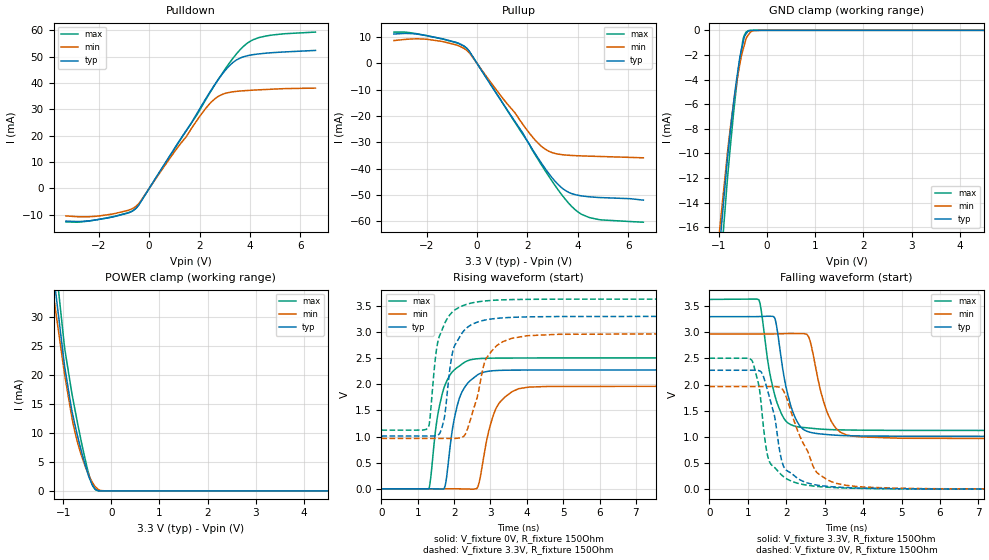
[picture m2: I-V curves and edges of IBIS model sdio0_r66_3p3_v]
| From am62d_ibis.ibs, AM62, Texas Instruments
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|   r66_3p3_v
[Model]   sdio0_r66_3p3_v
Model_type   I/O
Polarity   Non-Inverting
Enable   Active-High
Vinl = 0
Vinh = 0.8
Vmeas = 1.65
Vref = 3.3
Cref = 2pF
Rref = 100000
|   typ   min   max
C_comp   4.972pF   4.893pF   4.997pF
[Voltage Range]   3.3   2.97   3.63
[Temperature Range]   27   150   -40
[Pullup Reference]   3.3   2.97   3.63
[Pulldown Reference]   0   0   0
[Power Clamp Reference]   3.3   2.97   3.63
[GND Clamp Reference]   0   0   0
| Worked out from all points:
|   slope of the pulldown table from 0 to 0.495 V, typ, clamps not added: 65.7 ohm
|   slope of the pullup table from 0 to 0.495 V, typ, clamps not added: 67.2 ohm
|   GND clamp passes 1 mA (typ) near -0.50 V on its own axis
|   POWER clamp passes 1 mA (typ) near -0.39 V on its own axis
|   falling waveform, V_fixture 3.3V, R_fixture 150Ohm: 20-80 % time 372ps typ, 427ps min, 373ps max; typ from 3.3 V to 1.01 V
|   rising waveform, V_fixture 0V, R_fixture 150Ohm: 20-80 % time 360ps typ, 417ps min, 362ps max; typ from 0 V to 2.27 V
|   rising waveform, V_fixture 3.3V, R_fixture 150Ohm: 20-80 % time 346ps typ, 493ps min, 348ps max; typ from 1.01 V to 3.3 V
|   falling waveform, V_fixture 0V, R_fixture 150Ohm: 20-80 % time 382ps typ, 642ps min, 302ps max; typ from 2.27 V to 0 V
[Pulldown]
|   Voltage   I(typ)   I(min)   I(max)
-3.3V     -12.38mA   -10.4mA    -12.69mA
-1.924V   -11.64mA   -10.34mA   -11.61mA
-825mV    -9.287mA   -8.274mA   -9.181mA
-498.3mV  -7.317mA   -6.535mA   -7.277mA
1.917V    28.79mA    26.14mA    28.3mA
2.363V    35.87mA    31.75mA    35.58mA
2.779V    41.84mA    35.15mA    41.9mA
3.194V    46.68mA    36.49mA    47.74mA
3.442V    48.63mA    36.84mA    50.84mA
3.917V    50.43mA    37.21mA    55.3mA
4.363V    51.1mA     37.46mA    57.3mA
6.6V      52.41mA    38.1mA     59.37mA
[GND Clamp]
|   Voltage   I(typ)   I(min)   I(max)
-3.3V     -167.6mA   -127.2mA   -224.9mA
-1.013V   -18.75mA   -17.23mA   -21.53mA
-825mV    -10.45mA   -10mA      -12.11mA
-696.3mV  -5.878mA   -5.888mA   -6.706mA
-607.2mV  -3.274mA   -3.636mA   -3.487mA
-567.6mV  -2.201mA   -2.784mA   -2.433mA
-488.4mV  -791.1uA   -1.403mA   -562.6uA
-429mV    -244.1uA   -589.6uA   -116.9uA
-389.4mV  -55.69uA   -362.4uA   -20.74uA
-339.9mV  -13.09uA   -110.2uA   -2.892uA
-132mV    -51.23nA   -1.746uA   -80.05nA
6.6V      0A         0A         0A
[Pullup]
|   Voltage   I(typ)   I(min)   I(max)
-3.3V     11.17mA    8.678mA    11.89mA
-2.023V   10.59mA    9.208mA    10.6mA
-825mV    7.971mA    7.023mA    7.875mA
-409.2mV  5.742mA    4.947mA    5.744mA
1.502V    -22mA      -18.69mA   -22.32mA
2.056V    -30.43mA   -26.21mA   -30.36mA
2.363V    -35.1mA    -29.69mA   -35.55mA
2.838V    -41.68mA   -33.29mA   -42.71mA
3.472V    -48.02mA   -34.74mA   -51.2mA
4.026V    -50.09mA   -35.06mA   -56.53mA
4.462V    -50.64mA   -35.21mA   -58.53mA
6.6V      -51.89mA   -35.83mA   -60.27mA
[POWER Clamp]
|   Voltage   I(typ)   I(min)   I(max)
-3.3V     223mA      188.3mA    262.7mA
-1.201V   37.71mA    33.88mA    43.19mA
-1.191V   36.97mA    33.27mA    42.33mA
-1.152V   34.04mA    30.8mA     38.94mA
-983.4mV  22.42mA    20.88mA    25.69mA
-963.6mV  21.15mA    19.79mA    24.33mA
-805.2mV  13.3mA     12.07mA    16.24mA
-676.5mV  8.66mA     7.635mA    10.69mA
-488.4mV  3.032mA    3.154mA    3.565mA
-389.4mV  958.9uA    1.439mA    973.5uA
-290.4mV  115.2uA    394.7uA    56.84uA
6.6V      0A         0A         0A
[Ramp]
R_load = 150
|   typ   min   max
dV/dt_r   1.36452/3.60024e-10   1.17681/4.15033e-10   1.50275/3.61771e-10
dV/dt_f   1.37419/3.71447e-10   1.20297/4.24158e-10   1.50444/3.73096e-10
[Falling Waveform]
V_fixture = 3.3V
V_fixture_min = 2.97V
V_fixture_max = 3.63V
R_fixture = 150Ohm
C_fixture = 0F
|   Time   V(typ)   V(min)   V(max)
0s        3.3V       2.969V     3.63V
1.29ns    3.302V     2.969V     3.623V
1.545ns   3.307V     2.969V     2.334V
1.705ns   3.264V     2.97V      1.79V
1.96ns    2.082V     2.975V     1.333V
2.185ns   1.453V     2.977V     1.215V
2.58ns    1.097V     2.918V     1.171V
3.07ns    1.045V     1.464V     1.142V
3.565ns   1.024V     1.039V     1.132V
10ns      1.009V     964.3mV    1.122V
[Rising Waveform]
V_fixture = 0V
V_fixture_min = 0V
V_fixture_max = 0V
R_fixture = 150Ohm
C_fixture = 0F
|   Time   V(typ)   V(min)   V(max)
0s        421.7uV    878.7uV    305.1uV
1.305ns   333.2uV    642.3uV    6.835mV
1.525ns   -1.496mV   481.4uV    1.308V
1.725ns   4.128mV    457.7uV    1.938V
2.035ns   1.441V     -27.97uV   2.293V
2.37ns    2.018V     -3.796mV   2.45V
2.66ns    2.186V     53.71mV    2.489V
3.16ns    2.263V     1.546V     2.5V
3.775ns   2.271V     1.915V     2.502V
10ns      2.275V     1.962V     2.505V
[Rising Waveform]
V_fixture = 3.3V
V_fixture_min = 2.97V
V_fixture_max = 3.63V
R_fixture = 150Ohm
C_fixture = 0F
|   Time   V(typ)   V(min)   V(max)
0s        1.009V     964.3mV    1.122V
1.285ns   1.009V     964.2mV    1.167V
1.49ns    1.014V     964mV      2.532V
1.59ns    1.048V     964mV      2.912V
1.735ns   1.375V     964mV      3.155V
1.96ns    2.621V     963.9mV    3.387V
2.285ns   3.037V     1.021V     3.516V
2.865ns   3.23V      2.468V     3.595V
3.565ns   3.279V     2.874V     3.62V
10ns      3.3V       2.969V     3.63V
[Falling Waveform]
|Gnd
V_fixture = 0V
V_fixture_min = 0V
V_fixture_max = 0V
R_fixture = 150Ohm
C_fixture = 0F
|   Time   V(typ)   V(min)   V(max)
0s        2.275V     1.962V     2.505V
1.1ns     2.275V     1.962V     2.47V
1.295ns   2.266V     1.962V     1.954V
1.355ns   2.236V     1.962V     1.573V
1.56ns    1.767V     1.962V     530.2mV
1.9ns     500.3mV    1.912V     257.4mV
2.21ns    257.7mV    1.294V     132.9mV
2.755ns   83.96mV    358.1mV    56.31mV
3.34ns    38.74mV    104.8mV    27.67mV
10ns      420.5uV    878.9uV    305.3uV
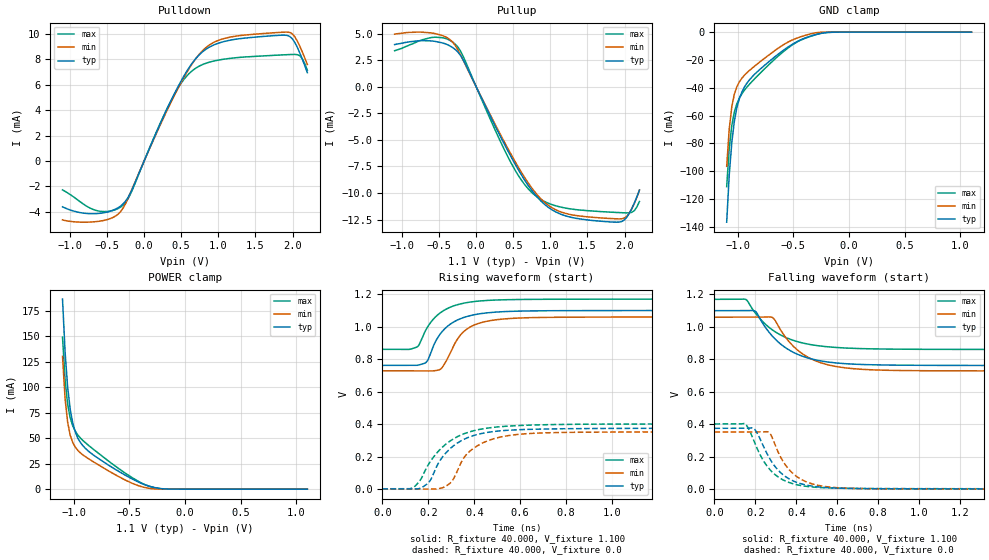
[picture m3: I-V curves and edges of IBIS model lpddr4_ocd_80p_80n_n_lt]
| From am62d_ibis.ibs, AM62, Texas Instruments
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|   Model lpddr4_ocd_80p_80n_n_lt
[Model] lpddr4_ocd_80p_80n_n_lt
Model_type I/O
Polarity   Non-Inverting
Enable   Active-High
Vinl =  0.113V
Vinh =  0.253V
Vmeas =  0.183V
C_comp   3.217pF   3.046pF   3.235pF
C_comp_pullup   0.301pF   0.290pF   0.305pF
C_comp_pulldown   1.279pF   1.206pF   1.283pF
[Model Spec]
Vinh   0.253V   0.247V   0.265V
Vinl   0.113V   0.107V   0.125V
Vmeas   0.183V   0.176V   0.195V
[Temperature Range]   25.000   -40.000   -40.000
[Voltage Range]   1.100V   1.060V   1.170V
[Pullup Reference]   1.100V   1.060V   1.170V
[Pulldown Reference]   0.0V   0.0V   0.0V
[C Comp Corner]
C_comp_pullup   0.301pF   0.290pF   0.305pF
C_comp_pulldown   1.279pF   1.206pF   1.283pF
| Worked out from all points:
|   slope of the pulldown table from 0 to 0.165 V, typ, clamps not added: 73.7 ohm
|   slope of the pullup table from 0 to 0.165 V, typ, clamps not added: 68.8 ohm
|   GND clamp passes 1 mA (typ) near -0.26 V on its own axis
|   POWER clamp passes 1 mA (typ) near -0.24 V on its own axis
|   rising waveform, R_fixture 40.000, V_fixture 1.100: 20-80 % time 106ps typ, 96.8ps min, 107ps max; typ from 0.762 V to 1.1 V
|   rising waveform, R_fixture 40.000, V_fixture 0.0: 20-80 % time 130ps typ, 122ps min, 150ps max; typ from 0.001 V to 0.375 V
|   falling waveform, R_fixture 40.000, V_fixture 1.100: 20-80 % time 178ps typ, 169ps min, 186ps max; typ from 1.1 V to 0.762 V
|   falling waveform, R_fixture 40.000, V_fixture 0.0: 20-80 % time 122ps typ, 117ps min, 119ps max; typ from 0.375 V to 0.001 V
[Pulldown]
|Voltage   I(typ)   I(min)   I(max)
-1.1V     -3.6mA     -4.624mA   -2.269mA
-624mV    -4.125mA   -4.747mA   -3.918mA
-284mV    -3.371mA   -3.705mA   -3.47mA
-181mV    -2.473mA   -2.447mA   -2.564mA
227mV     3.052mA    2.956mA    3.092mA
465mV     5.929mA    5.803mA    5.81mA
703mV     8.095mA    8.097mA    7.323mA
907mV     9.036mA    9.222mA    7.813mA
1.928V    9.87mA     10.13mA    8.358mA
1.996V    9.616mA    10mA       8.375mA
2.098V    8.498mA    9.025mA    8.273mA
2.2V      6.944mA    7.59mA     7.136mA
[Pullup]
|Voltage   I(typ)   I(min)   I(max)
-1.1V     3.978mA    4.962mA    3.399mA
-590mV    4.31mA     5.055mA    4.652mA
-284mV    3.52mA     3.909mA    4.021mA
-147mV    2.159mA    2.092mA    2.416mA
295mV     -4.237mA   -4.07mA    -4.673mA
533mV     -7.385mA   -7.144mA   -7.949mA
737mV     -9.638mA   -9.409mA   -9.867mA
1.009V    -11.52mA   -11.33mA   -11.06mA
1.315V    -12.34mA   -12.09mA   -11.54mA
1.928V    -12.73mA   -12.44mA   -11.84mA
2.064V    -11.91mA   -11.88mA   -11.86mA
2.2V      -9.724mA   -9.725mA   -10.8mA
[GND_clamp]
|Voltage   I(typ)   I(min)   I(max)
-1.1V     -136.6mA   -96.46mA   -111.1mA
-1.077V   -102.6mA   -69.55mA   -83.57mA
-1.054V   -79.22mA   -53.64mA   -67.05mA
-1.031V   -63.93mA   -44.56mA   -57.36mA
-1.008V   -54.04mA   -39.16mA   -51.37mA
-985mV    -47.47mA   -35.61mA   -47.28mA
-940mV    -39.36mA   -30.91mA   -41.63mA
-894mV    -34.19mA   -27.47mA   -37.37mA
-642mV    -16.16mA   -11.85mA   -17.57mA
-435mV    -5.566mA   -3.394mA   -5.8mA
-206mV    -368.5uA   -17.49uA   -340.6uA
1.1V      0A         0A         0A
[POWER_clamp]
|Voltage   I(typ)   I(min)   I(max)
-1.1V     186.7mA    130.4mA    149.4mA
-1.077V   134.7mA    89.1mA     107.4mA
-1.054V   100.3mA    65.79mA    83.44mA
-1.031V   78.51mA    53mA       69.97mA
-1.008V   64.87mA    45.79mA    62.12mA
-963mV    50.23mA    38.14mA    53.29mA
-917mV    42.67mA    33.66mA    47.79mA
-848mV    35.63mA    28.64mA    41.42mA
-481mV    10.42mA    6.123mA    11.78mA
-367mV    4.613mA    1.825mA    4.83mA
-252mV    1.166mA    119.4uA    981uA
1.1V      0A         0A         0A
[Ramp]
| variable   typ   min   max
dV/dt_r   0.232/98.871p   0.220/90.180p   0.253/0.105n
dV/dt_f   0.232/0.216n   0.219/0.206n   0.253/0.227n
R_load = 40.000
[Rising Waveform]
R_fixture= 40.000
V_fixture= 1.100
V_fixture_min= 1.060
V_fixture_max= 1.170
|time   V(typ)   V(min)   V(max)
0s        761.9mV    728.5mV    860.7mV
148ps     761.7mV    728.5mV    873.1mV
186ps     776.2mV    728.3mV    971.1mV
249ps     949.6mV    735.3mV    1.082V
296ps     1.016V     838.9mV    1.12V
327ps     1.041V     924.2mV    1.135V
361ps     1.06V      978mV      1.147V
426ps     1.08V      1.023V     1.158V
526ps     1.092V     1.047V     1.166V
5ns       1.1V       1.06V      1.17V
[Rising Waveform]
R_fixture= 40.000
V_fixture= 0.0
V_fixture_min= 0.0
V_fixture_max= 0.0
|time   V(typ)   V(min)   V(max)
0s        1.134mV    70.35uV    2.405mV
137ps     1.013mV    70.11uV    12.8mV
166ps     6.25mV     71.57uV    57.66mV
203ps     43.73mV    19.24uV    157.7mV
267ps     207.6mV    11.72mV    265.8mV
303ps     259.2mV    49.71mV    304.1mV
352ps     304.6mV    187.3mV    339.2mV
393ps     328.2mV    247.4mV    358.1mV
568ps     364.3mV    333.5mV    389.9mV
5ns       375.3mV    354.1mV    401.8mV
[Falling Waveform]
R_fixture= 40.000
V_fixture= 1.100
V_fixture_min= 1.060
V_fixture_max= 1.170
|time   V(typ)   V(min)   V(max)
0s        1.1V       1.06V      1.17V
151ps     1.1V       1.06V      1.17V
197ps     1.098V     1.06V      1.09V
281ps     945.9mV    1.059V     983.4mV
364ps     858.3mV    909.9mV    926.8mV
438ps     815.8mV    827.5mV    898.9mV
536ps     787mV      772.7mV    879.6mV
668ps     771.2mV    743.8mV    868.4mV
1.117ns   762.7mV    729.4mV    861.5mV
5ns       761.9mV    728.5mV    860.7mV
[Falling Waveform]
R_fixture= 40.000
V_fixture= 0.0
V_fixture_min= 0.0
V_fixture_max= 0.0
|time   V(typ)   V(min)   V(max)
0s        375.1mV    352.2mV    401.8mV
151ps     375mV      352.2mV    401.8mV
197ps     368.4mV    352.2mV    285.1mV
264ps     202.2mV    351.1mV    131.1mV
312ps     116.1mV    226.4mV    74.67mV
370ps     59.78mV    113.6mV    38.76mV
429ps     31.19mV    56.91mV    20.99mV
507ps     14.17mV    23.58mV    10.68mV
877ps     2.46mV     1.451mV    3.46mV
5ns       1.147mV    70.82uV    2.412mV
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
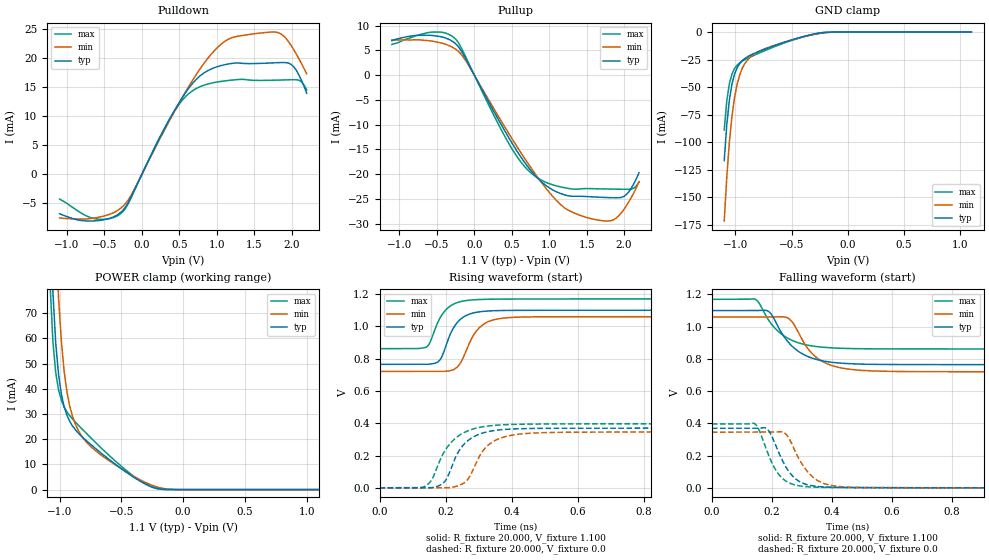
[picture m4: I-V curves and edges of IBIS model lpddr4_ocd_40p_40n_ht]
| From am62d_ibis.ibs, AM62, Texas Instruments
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|LPDDR4 ********** End LPDDR4 LT Models
|LPDDR4 ********** Begin LPDDR4 HT Models
|   Model lpddr4_ocd_40p_40n_ht
[Model] lpddr4_ocd_40p_40n_ht
Model_type I/O
Polarity   Non-Inverting
Enable   Active-High
Vinl =  0.113V
Vinh =  0.253V
Vmeas =  0.183V
C_comp   2.128pF   2.068pF   2.214pF
[Model Spec]
Vinh   0.253V   0.247V   0.265V
Vinl   0.113V   0.107V   0.125V
Vmeas   0.183V   0.176V   0.195V
[Temperature Range]   25.000   0.125k   -40.000
[Voltage Range]   1.100V   1.060V   1.170V
[Pullup Reference]   1.100V   1.060V   1.170V
[Pulldown Reference]   0.0V   0.0V   0.0V
[C Comp Corner]
C_comp   2.128pF   2.068pF   2.214pF
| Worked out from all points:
|   slope of the pulldown table from 0 to 0.165 V, typ, clamps not added: 37.7 ohm
|   slope of the pullup table from 0 to 0.165 V, typ, clamps not added: 35.3 ohm
|   GND clamp passes 1 mA (typ) near -0.26 V on its own axis
|   POWER clamp passes 1 mA (typ) near -0.24 V on its own axis
|   rising waveform, R_fixture 20.000, V_fixture 1.100: 20-80 % time 46.6ps typ, 53.4ps min, 46.5ps max; typ from 0.765 V to 1.1 V
|   rising waveform, R_fixture 20.000, V_fixture 0.0: 20-80 % time 62ps typ, 64.4ps min, 71.1ps max; typ from 0.001 V to 0.37 V
|   falling waveform, R_fixture 20.000, V_fixture 1.100: 20-80 % time 89.6ps typ, 83.9ps min, 89.3ps max; typ from 1.1 V to 0.765 V
|   falling waveform, R_fixture 20.000, V_fixture 0.0: 20-80 % time 62.9ps typ, 69.5ps min, 58.3ps max; typ from 0.37 V to 0.001 V
[Pulldown]
|Voltage   I(typ)   I(min)   I(max)
-1.1V     -6.798mA   -7.521mA   -4.288mA
-658mV    -8.043mA   -7.581mA   -7.565mA
-284mV    -6.568mA   -5.855mA   -6.785mA
-147mV    -3.977mA   -3.669mA   -4.118mA
261mV     6.826mA    6.606mA    6.92mA
533mV     13.06mA    13.05mA    12.63mA
805mV     17.19mA    18.64mA    15.19mA
1.145V    18.92mA    23.14mA    16.1mA
1.826V    19.17mA    24.29mA    16.17mA
2.03V     18.41mA    21.33mA    16.24mA
2.132V    16.08mA    18.96mA    15.87mA
2.2V      13.9mA     17.26mA    14.49mA
[Pullup]
|Voltage   I(typ)   I(min)   I(max)
-1.1V     6.941mA    7.09mA     6.183mA
-590mV    8.025mA    6.904mA    8.63mA
-284mV    6.736mA    5.549mA    7.721mA
-113mV    3.254mA    2.882mA    3.632mA
329mV     -9.187mA   -8.507mA   -10.13mA
601mV     -16.06mA   -15.17mA   -17.12mA
907mV     -21.69mA   -21.89mA   -21.3mA
1.247V    -24.36mA   -27.22mA   -22.87mA
1.588V    -24.61mA   -29.09mA   -22.95mA
1.86V     -24.78mA   -29.21mA   -23.03mA
2.03V     -24.15mA   -26.41mA   -23.07mA
2.2V      -19.71mA   -21.51mA   -21.55mA
[GND_clamp]
|Voltage   I(typ)   I(min)   I(max)
-1.1V     -116.8mA   -171.6mA   -88.94mA
-1.077V   -83.96mA   -131.3mA   -62.39mA
-1.054V   -61.6mA    -99.87mA   -46.82mA
-1.031V   -47.19mA   -76.34mA   -38.11mA
-1.008V   -38.16mA   -59.32mA   -33.12mA
-985mV    -32.43mA   -47.3mA    -30.04mA
-940mV    -26mA      -32.95mA   -26.37mA
-894mV    -22.48mA   -25.52mA   -23.91mA
-848mV    -20.08mA   -21.13mA   -21.75mA
-619mV    -11.17mA   -10.91mA   -11.97mA
-229mV    -598.7uA   -1.001mA   -573.1uA
1.1V      0A         0A         0A
[POWER_clamp]
|Voltage   I(typ)   I(min)   I(max)
-1.1V     158.5mA    248.7mA    122.8mA
-1.077V   110.5mA    184.5mA    81.81mA
-1.054V   78.43mA    136mA      58.82mA
-1.031V   58.13mA    100.8mA    46.37mA
-1.008V   45.61mA    75.97mA    39.54mA
-985mV    37.81mA    58.74mA    35.43mA
-963mV    32.84mA    46.93mA    32.78mA
-940mV    29.44mA    38.74mA    30.81mA
-871mV    23.65mA    25.79mA    26.71mA
-642mV    13.62mA    12.94mA    15.51mA
-206mV    448.9uA    953.5uA    285.6uA
1.1V      0A         0A         0A
[Ramp]
| variable   typ   min   max
dV/dt_r   0.222/62.046p   0.208/64.382p   0.238/71.086p
dV/dt_f   0.201/89.565p   0.204/84.088p   0.185/89.279p
R_load = 20.000
[Rising Waveform]
R_fixture= 20.000
V_fixture= 1.100
V_fixture_min= 1.060
V_fixture_max= 1.170
|time   V(typ)   V(min)   V(max)
0s        764.9mV    720.8mV    861.9mV
142ps     764.7mV    720.8mV    872.2mV
152ps     766.3mV    720.8mV    898.4mV
183ps     793.7mV    720.5mV    1.052V
223ps     988.3mV    731.4mV    1.137V
245ps     1.044V     775.2mV    1.153V
295ps     1.088V     976.5mV    1.165V
350ps     1.097V     1.043V     1.168V
548ps     1.099V     1.059V     1.169V
5ns       1.1V       1.06V      1.17V
[Rising Waveform]
R_fixture= 20.000
V_fixture= 0.0
V_fixture_min= 0.0
V_fixture_max= 0.0
|time   V(typ)   V(min)   V(max)
0s        557.8uV    842.1uV    1.185mV
141ps     573.8uV    838.4uV    14.95mV
160ps     2.108mV    832.9uV    58.59mV
196ps     36.82mV    899.9uV    224.3mV
243ps     238.1mV    17.6mV     327.8mV
269ps     296mV      59.48mV    355.2mV
323ps     346.1mV    254.3mV    381.9mV
390ps     363.5mV    322.2mV    392.2mV
650ps     369.6mV    345.5mV    396.8mV
5ns       370.3mV    347mV      397.2mV
[Falling Waveform]
R_fixture= 20.000
V_fixture= 1.100
V_fixture_min= 1.060
V_fixture_max= 1.170
|time   V(typ)   V(min)   V(max)
0s        1.1V       1.06V      1.17V
146ps     1.1V       1.06V      1.169V
192ps     1.09V      1.06V      1.033V
249ps     916.9mV    1.058V     932.6mV
270ps     874.6mV    1.024V     912.9mV
294ps     840.3mV    943.4mV    897mV
351ps     795.7mV    805.4mV    876.4mV
403ps     778.6mV    757.3mV    868.4mV
477ps     769.3mV    732.6mV    864mV
5ns       764.9mV    720.8mV    861.9mV
[Falling Waveform]
R_fixture= 20.000
V_fixture= 0.0
V_fixture_min= 0.0
V_fixture_max= 0.0
|time   V(typ)   V(min)   V(max)
0s        369.8mV    345.9mV    396.8mV
144ps     369.7mV    345.9mV    396.8mV
188ps     358.1mV    345.8mV    208.2mV
212ps     267.5mV    347.2mV    113.7mV
238ps     159.8mV    344.9mV    54.66mV
280ps     54.64mV    217.9mV    17.41mV
339ps     12.17mV    63.51mV    5.223mV
402ps     3.902mV    14mV       2.716mV
539ps     1.466mV    2.153mV    1.722mV
5ns       557.6uV    836uV      1.186mV
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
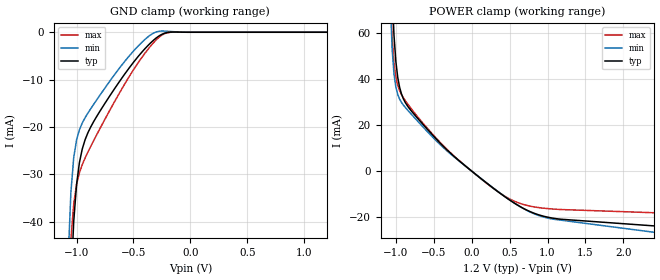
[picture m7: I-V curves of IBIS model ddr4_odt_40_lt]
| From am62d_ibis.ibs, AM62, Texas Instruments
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|   Model ddr4_odt_40_lt
[Model] ddr4_odt_40_lt
Model_type Input
Polarity   Non-Inverting
Enable   Active-High
Vinl =  0.700V
Vinh =  0.900V
C_comp   2.181pF   1.976pF   2.362pF
[Model Spec]
Vinh   0.900V   0.820V   0.980V
Vinl   0.700V   0.620V   0.780V
[Temperature Range]   25.000   -40.000   -40.000
[Voltage Range]   1.200V   1.140V   1.260V
[C Comp Corner]
C_comp   2.181pF   1.976pF   2.362pF
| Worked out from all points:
|   GND clamp passes 1 mA (typ) near -0.29 V on its own axis
|   POWER clamp passes 1 mA (typ) near -0.04 V on its own axis
[GND_clamp]
|Voltage   I(typ)   I(min)   I(max)
-1.2V     -384.2mA   -349.1mA   -361.3mA
-1.075V   -75.51mA   -48.36mA   -58.73mA
-1.05V    -53.29mA   -33.77mA   -43.81mA
-1.025V   -39.9mA    -26.45mA   -36.16mA
-1V       -32.1mA    -22.71mA   -32.11mA
-975mV    -27.5mA    -20.58mA   -29.67mA
-950mV    -24.63mA   -19.15mA   -27.94mA
-875mV    -19.96mA   -16.12mA   -24.06mA
-750mV    -14.97mA   -11.74mA   -18.32mA
-350mV    -2.263mA   -565uA     -2.938mA
-175mV    27.08uA    163.2uA    -8.172uA
1.2V      0A         0A         0A
[POWER_clamp]
|Voltage   I(typ)   I(min)   I(max)
-1.2V     599.9mA    618.7mA    627.1mA
-1.075V   111.9mA    76.22mA    81.9mA
-1.05V    79.07mA    53.64mA    58.84mA
-1.025V   59.3mA     42.37mA    47.11mA
-1V       47.67mA    36.58mA    40.91mA
-950mV    36.4mA     31.3mA     34.98mA
-900mV    31.43mA    28.72mA    31.9mA
-325mV    9.238mA    8.792mA    9.428mA
375mV     -9.667mA   -9.572mA   -9.635mA
650mV     -15.66mA   -15.71mA   -14.21mA
1V        -20.04mA   -20.43mA   -16.31mA
2.4V      -23.84mA   -26.61mA   -18.12mA
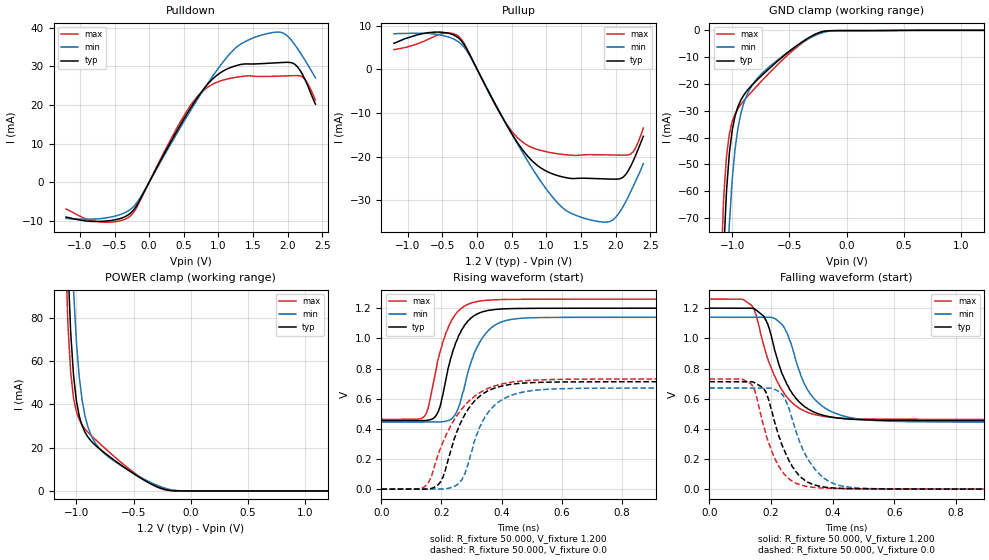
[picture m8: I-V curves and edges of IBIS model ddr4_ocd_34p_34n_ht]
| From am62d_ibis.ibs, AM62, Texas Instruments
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|DDR4 ********** End DDR4 LT Models
|DDR4 ********** Begin DDR4 HT Models
|   Model ddr4_ocd_34p_34n_ht
[Model] ddr4_ocd_34p_34n_ht
Model_type I/O
Polarity   Non-Inverting
Enable   Active-High
Vinl =  0.700V
Vinh =  0.900V
Vmeas =  0.600V
C_comp   2.033pF   1.992pF   2.166pF
[Model Spec]
Vinh   0.900V   0.820V   0.980V
Vinl   0.700V   0.620V   0.780V
Vmeas   0.600V   NA   NA
[Temperature Range]   25.000   0.125k   -40.000
[Voltage Range]   1.200V   1.140V   1.260V
[Pullup Reference]   1.200V   1.140V   1.260V
[Pulldown Reference]   0.0V   0.0V   0.0V
[C Comp Corner]
C_comp   2.033pF   1.992pF   2.166pF
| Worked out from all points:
|   slope of the pulldown table from 0 to 0.18 V, typ, clamps not added: 29.6 ohm
|   slope of the pullup table from 0 to 0.18 V, typ, clamps not added: 32.3 ohm
|   GND clamp passes 1 mA (typ) near -0.25 V on its own axis
|   POWER clamp passes 1 mA (typ) near -0.25 V on its own axis
|   rising waveform, R_fixture 50.000, V_fixture 1.200: 20-80 % time 64.1ps typ, 72ps min, 64.6ps max; typ from 0.455 V to 1.2 V
|   rising waveform, R_fixture 50.000, V_fixture 0.0: 20-80 % time 89.4ps typ, 83.8ps min, 116ps max; typ from 0.001 V to 0.713 V
|   falling waveform, R_fixture 50.000, V_fixture 1.200: 20-80 % time 84ps typ, 88.9ps min, 88.7ps max; typ from 1.2 V to 0.455 V
|   falling waveform, R_fixture 50.000, V_fixture 0.0: 20-80 % time 76.3ps typ, 83.7ps min, 70.4ps max; typ from 0.713 V to 0.001 V
[Pulldown]
|Voltage   I(typ)   I(min)   I(max)
-1.2V     -9.006mA   -9.388mA   -6.947mA
-718mV    -10.14mA   -9.441mA   -10.24mA
-272mV    -8.055mA   -7.047mA   -8.751mA
-124mV    -4.222mA   -3.864mA   -4.561mA
359mV     11.91mA    11.33mA    12.65mA
656mV     20.78mA    20.23mA    21.27mA
990mV     27.82mA    29.26mA    25.93mA
1.361V    30.56mA    36.13mA    27.4mA
1.955V    30.99mA    38.38mA    27.48mA
2.14V     29.85mA    34.61mA    27.57mA
2.252V    26.49mA    31.49mA    26.52mA
2.4V      20.19mA    26.99mA    21.28mA
[Pullup]
|Voltage   I(typ)   I(min)   I(max)
-1.2V     5.943mA    8.121mA    4.494mA
-606mV    8.496mA    8.044mA    7.591mA
-421mV    8.267mA    7.423mA    8.349mA
-235mV    6.663mA    5.861mA    7.043mA
322mV     -9.774mA   -9.622mA   -9.826mA
544mV     -15.84mA   -15.99mA   -14.99mA
878mV     -22.09mA   -24.67mA   -18.39mA
1.324V    -24.91mA   -32.69mA   -19.62mA
1.955V    -25.14mA   -34.51mA   -19.61mA
2.103V    -24.74mA   -31.54mA   -19.65mA
2.252V    -21.04mA   -26.85mA   -18.9mA
2.4V      -15.33mA   -21.56mA   -13.45mA
[GND_clamp]
|Voltage   I(typ)   I(min)   I(max)
-1.2V     -396.3mA   -450.8mA   -370.1mA
-1.1V     -118.3mA   -172.8mA   -91.09mA
-1.075V   -83.02mA   -129.3mA   -62.73mA
-1.05V    -59.94mA   -96.19mA   -46.97mA
-1.025V   -45.76mA   -72.24mA   -38.62mA
-1V       -37.22mA   -55.56mA   -33.98mA
-975mV    -31.95mA   -44.18mA   -31.14mA
-925mV    -26.07mA   -31.12mA   -27.64mA
-775mV    -18.22mA   -17.64mA   -20.37mA
-425mV    -5.392mA   -5.54mA    -5.964mA
-175mV    -232.3uA   -493.9uA   -237.1uA
1.2V      0A         0A         0A
[POWER_clamp]
|Voltage   I(typ)   I(min)   I(max)
-1.2V     594.8mA    732.7mA    623.3mA
-1.1V     157.8mA    248.4mA    121.5mA
-1.075V   106.2mA    179.2mA    77.8mA
-1.05V    73.23mA    128.5mA    54.67mA
-1.025V   53.34mA    92.89mA    42.85mA
-1V       41.61mA    68.72mA    36.57mA
-975mV    34.56mA    52.6mA     32.87mA
-925mV    27.12mA    34.66mA    28.61mA
-825mV    20.64mA    21.33mA    23.28mA
-675mV    14.44mA    14mA       16.15mA
-200mV    388.2uA    876.1uA    237.4uA
1.2V      0A         0A         0A
[Ramp]
| variable   typ   min   max
dV/dt_r   0.427/89.561p   0.432/87.187p   0.437/0.117n
dV/dt_f   0.447/84.662p   0.446/91.796p   0.478/88.149p
R_load = 60.000
[Rising Waveform]
R_fixture= 50.000
V_fixture= 1.200
V_fixture_min= 1.140
V_fixture_max= 1.260
|time   V(typ)   V(min)   V(max)
0s        455.2mV    445.7mV    463.4mV
143ps     455.3mV    445.7mV    483.7mV
155ps     457.8mV    445.7mV    532.8mV
190ps     518mV      445.7mV    868.7mV
236ps     900.2mV    471.1mV    1.127V
276ps     1.085V     674mV      1.213V
333ps     1.173V     991.7mV    1.249V
396ps     1.194V     1.106V     1.257V
506ps     1.199V     1.137V     1.259V
3ns       1.2V       1.14V      1.26V
[Rising Waveform]
R_fixture= 50.000
V_fixture= 0.0
V_fixture_min= 0.0
V_fixture_max= 0.0
|time   V(typ)   V(min)   V(max)
0s        1.434mV    1.61mV     2.494mV
139ps     1.37mV     1.6mV      11.11mV
162ps     4.513mV    1.591mV    65.51mV
187ps     27.16mV    1.528mV    218.5mV
205ps     79.98mV    2.312mV    314.7mV
255ps     399.3mV    34.26mV    499.3mV
278ps     497.6mV    103.8mV    556.5mV
345ps     640.8mV    480.6mV    659.5mV
444ps     698.5mV    630.4mV    712.7mV
3ns       712.8mV    671.4mV    731.1mV
[Falling Waveform]
R_fixture= 50.000
V_fixture= 1.200
V_fixture_min= 1.140
V_fixture_max= 1.260
|time   V(typ)   V(min)   V(max)
0s        1.2V       1.14V      1.26V
139ps     1.199V     1.14V      1.213V
184ps     1.12V      1.14V      895.5mV
217ps     885.3mV    1.124V     728.2mV
251ps     698.1mV    1.041V     612mV
279ps     606.4mV    868.3mV    555.6mV
315ps     539.6mV    669.7mV    512.9mV
380ps     484.7mV    532.7mV    480.4mV
645ps     456.1mV    448.3mV    463.9mV
3ns       455.2mV    445.6mV    463.4mV
[Falling Waveform]
R_fixture= 50.000
V_fixture= 0.0
V_fixture_min= 0.0
V_fixture_max= 0.0
|time   V(typ)   V(min)   V(max)
0s        712.8mV    671.3mV    731.1mV
136ps     712.6mV    671.3mV    697.2mV
183ps     647.6mV    671.3mV    370.5mV
228ps     339mV      644.8mV    144.8mV
251ps     221.3mV    574.7mV    82.29mV
278ps     123.6mV    401.8mV    44.64mV
331ps     36.75mV    165.7mV    14.79mV
402ps     9.12mV     38.96mV    6.159mV
512ps     3.266mV    6.029mV    3.739mV
3ns       1.433mV    1.604mV    2.494mV
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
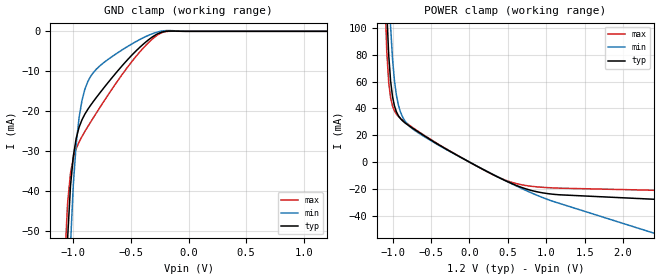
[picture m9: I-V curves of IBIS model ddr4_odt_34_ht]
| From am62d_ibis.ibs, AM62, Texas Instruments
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|   Model ddr4_odt_34_ht
[Model] ddr4_odt_34_ht
Model_type Input
Polarity   Non-Inverting
Enable   Active-High
Vinl =  0.700V
Vinh =  0.900V
C_comp   2.071pF   1.974pF   2.274pF
[Model Spec]
Vinh   0.900V   0.820V   0.980V
Vinl   0.700V   0.620V   0.780V
[Temperature Range]   25.000   0.125k   -40.000
[Voltage Range]   1.200V   1.140V   1.260V
[C Comp Corner]
C_comp   2.071pF   1.974pF   2.274pF
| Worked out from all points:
|   GND clamp passes 1 mA (typ) near -0.29 V on its own axis
|   POWER clamp passes 1 mA (typ) near -0.03 V on its own axis
[GND_clamp]
|Voltage   I(typ)   I(min)   I(max)
-1.2V     -382.1mA   -423.2mA   -359.6mA
-1.075V   -74.28mA   -108.5mA   -57.99mA
-1.05V    -52.21mA   -76.65mA   -43.22mA
-1.025V   -38.97mA   -53.95mA   -35.73mA
-1V       -31.31mA   -38.46mA   -31.79mA
-975mV    -26.84mA   -28.25mA   -29.44mA
-925mV    -22.21mA   -17.36mA   -26.4mA
-850mV    -18.56mA   -11.31mA   -22.79mA
-700mV    -12.92mA   -7.087mA   -16.04mA
-425mV    -4.063mA   -2.088mA   -5.239mA
-225mV    -150.9uA   95.96uA    -261.9uA
1.2V      0A         0A         0A
[POWER_clamp]
|Voltage   I(typ)   I(min)   I(max)
-1.2V     600.8mA    740.8mA    627.8mA
-1.1V     164.3mA    256.6mA    126.2mA
-1.075V   112.9mA    187.3mA    82.65mA
-1.05V    80.14mA    136.6mA    59.6mA
-1.025V   60.4mA     101.1mA    47.88mA
-1V       48.79mA    76.9mA     41.69mA
-975mV    41.87mA    60.78mA    38.11mA
-925mV    34.67mA    42.86mA    34.11mA
-825mV    28.64mA    29.56mA    29.31mA
-325mV    10.39mA    10.1mA     10.62mA
675mV     -18.83mA   -19.57mA   -16.88mA
2.4V      -27.74mA   -52.99mA   -21.04mA
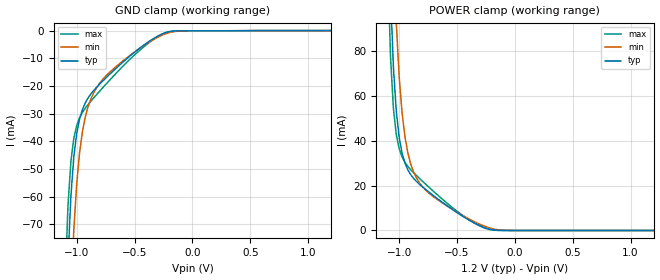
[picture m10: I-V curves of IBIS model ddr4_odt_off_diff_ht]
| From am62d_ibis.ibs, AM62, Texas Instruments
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|   Model ddr4_odt_off_diff_ht
[Model] ddr4_odt_off_diff_ht
Model_type Input
Polarity   Non-Inverting
Enable   Active-High
Vinl =  0.700V
Vinh =  0.900V
C_comp   2.961pF   2.937pF   3.050pF
[Model Spec]
Vinh   0.900V   0.820V   0.980V
Vinl   0.700V   0.620V   0.780V
[Temperature Range]   25.000   0.125k   -40.000
[Voltage Range]   1.200V   1.140V   1.260V
[C Comp Corner]
C_comp   2.961pF   3.050pF   2.937pF
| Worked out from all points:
|   GND clamp passes 1 mA (typ) near -0.25 V on its own axis
|   POWER clamp passes 1 mA (typ) near -0.25 V on its own axis
[GND_clamp]
|Voltage   I(typ)   I(min)   I(max)
-1.2V     -396.3mA   -450.8mA   -370.5mA
-1.1V     -118.3mA   -172.8mA   -91.45mA
-1.075V   -83.01mA   -129.2mA   -63.09mA
-1.05V    -59.94mA   -96.17mA   -47.34mA
-1.025V   -45.76mA   -72.23mA   -38.98mA
-1V       -37.22mA   -55.55mA   -34.35mA
-975mV    -31.96mA   -44.18mA   -31.5mA
-925mV    -26.08mA   -31.12mA   -27.98mA
-775mV    -18.23mA   -17.65mA   -20.66mA
-425mV    -5.396mA   -5.544mA   -6.053mA
-175mV    -232.4uA   -494uA     -237.3uA
1.2V      0A         0A         0A
[POWER_clamp]
|Voltage   I(typ)   I(min)   I(max)
-1.2V     594.8mA    732.7mA    623.3mA
-1.1V     157.8mA    248.4mA    121.5mA
-1.075V   106.2mA    179.2mA    77.82mA
-1.05V    73.23mA    128.5mA    54.69mA
-1.025V   53.35mA    92.88mA    42.87mA
-1V       41.61mA    68.71mA    36.59mA
-975mV    34.57mA    52.59mA    32.89mA
-925mV    27.12mA    34.66mA    28.63mA
-825mV    20.64mA    21.33mA    23.3mA
-675mV    14.46mA    14.01mA    16.17mA
-200mV    388.2uA    876.3uA    237.2uA
1.2V      0A         0A         0A
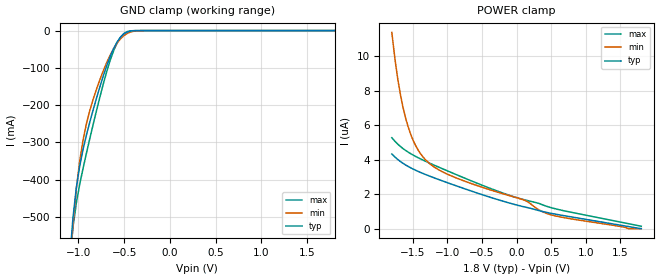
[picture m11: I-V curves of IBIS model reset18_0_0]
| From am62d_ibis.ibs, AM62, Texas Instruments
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|**************** Begin RESET ******************************************
|   Model reset18_0_0
[Model]  reset18_0_0
Model_type Input
Polarity   Non-Inverting
Enable   Active-High
Vinl =  0.580V
Vinh =  1.270V
C_comp   5.938pF   5.749pF   6.083pF
[Model Spec]
Vinh   1.270V   1.270V   1.270V
Vinl   0.580V   0.580V   0.580V
[Temperature Range]   25.000   0.125k   -40.000
[Voltage Range]   1.800V   1.620V   1.980V
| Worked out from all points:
|   GND clamp passes 1 mA (typ) near -0.42 V on its own axis
[GND_clamp]
|Voltage   I(typ)   I(min)   I(max)
-1.8V     -5.494A    -4.834A    -6.125A
-1.097V   -617.7mA   -644.2mA   -627.1mA
-1.06V    -503.4mA   -522.3mA   -528.6mA
-1.023V   -421.8mA   -424.6mA   -462.9mA
-986mV    -363.5mA   -349.7mA   -412.9mA
-949mV    -318.3mA   -293.1mA   -369.4mA
-875mV    -244.9mA   -213.9mA   -289.1mA
-653mV    -69.37mA   -65.95mA   -79.89mA
-579mV    -31.34mA   -34.43mA   -33.73mA
-505mV    -9.302mA   -13.88mA   -8.255mA
-320mV    -34.12uA   -277.7uA   -6.542uA
1.8V      0A         0A         0A
[POWER_clamp]
|Voltage   I(typ)   I(min)   I(max)
-1.8V     4.337uA    11.4uA     5.281uA
-1.752V   4.15uA     9.768uA    5.062uA
-1.678V   3.905uA    7.835uA    4.779uA
-1.567V   3.618uA    5.947uA    4.453uA
-1.493V   3.462uA    5.135uA    4.276uA
-1.419V   3.323uA    4.557uA    4.118uA
-1.234V   3.02uA     3.713uA    3.769uA
-790mV    2.375uA    2.821uA    3.004uA
135mV     1.243uA    1.616uA    1.655uA
468mV     914.5nA    839.9nA    1.256uA
1.615V    122.3nA    0A         288.3nA
1.8V      0A         0A         139.5nA
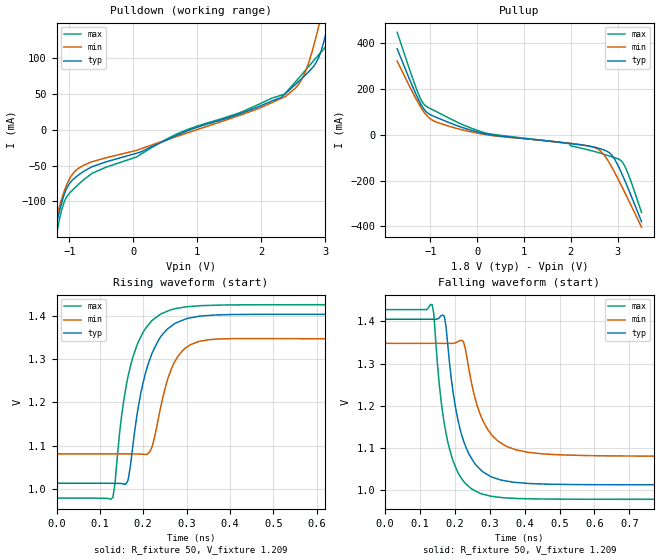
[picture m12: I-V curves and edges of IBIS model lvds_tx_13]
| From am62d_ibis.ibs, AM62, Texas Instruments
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|   MODEL lvds_tx_13
[Model] lvds_tx_13
Model_type Output
C_comp 1.683p 1.744p 1.546p
Vmeas = 1.2
Vref = 1.2V
Rref = 50
Cref = 0.5pF
[Model Spec]
[Temperature Range]  40 150 -40
[Voltage Range] 1.8 1.62 1.98
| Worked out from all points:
|   slope of the pulldown table from 0 to 0.27 V, typ, clamps not added: 27.6 ohm
|   slope of the pullup table from 0 to 0.27 V, typ, clamps not added: 21.9 ohm
|   rising waveform, R_fixture 50, V_fixture 1.209: 20-80 % time 50.8ps typ, 43.3ps min, 47.8ps max; typ from 1.01 V to 1.4 V
|   falling waveform, R_fixture 50, V_fixture 1.209: 20-80 % time 55.4ps typ, 64.2ps min, 48.8ps max; typ from 1.41 V to 1.01 V
[Pulldown]
-1.71V    -379.2mA   -326.8mA   -450.1mA
-1.272V   -162.2mA   -148mA     -183.8mA
-1.208V   -134.8mA   -125.2mA   -150.2mA
-1.04V    -81.66mA   -76.62mA   -93.66mA
-849.5mV  -62.76mA   -53.47mA   -75.75mA
681.3mV   -7.804mA   -9.398mA   -5.773mA
2.381V    50.71mA    46.73mA    51.65mA
2.666V    74.58mA    76.43mA    80.72mA
2.898V    101.5mA    145.2mA    104.9mA
3.03V     142.8mA    196mA      118.6mA
3.162V    200.5mA    249.9mA    145.6mA
3.511V    373.6mA    396.2mA    335.3mA
[Pullup]
-1.711V   373.6mA    320.5mA    445.8mA
-1.273V   160.2mA    143mA      185.7mA
-1.098V   101.5mA    88.1mA     124.9mA
-660.3mV  57.23mA    40.13mA    78mA
187.1mV   2.713mA    0A         6.903mA
1.979V    -38.6mA    -37.71mA   -39.55mA
2.56V     -57.35mA   -60.89mA   -76.35mA
2.702V    -66.46mA   -86.65mA   -85.16mA
2.861V    -86.01mA   -136.6mA   -95.46mA
3.109V    -179.1mA   -234mA     -122mA
3.272V    -258.6mA   -302.5mA   -197mA
3.51V     -379.2mA   -402.9mA   -338.7mA
[Ramp]
dV/dt_r .235/51.092p .16/43.407p .27/47.61p
dV/dt_f .235/55.216p .16/63.929p .27/48.766p
[Rising Waveform]
R_fixture = 50
V_fixture = 1.209
V_fixture_min = 1.214
V_fixture_max = 1.203
0s        1.013V     1.081V     978.2mV
130ps     1.012V     1.081V     979.7mV
160ps     1.011V     1.081V     1.235V
170ps     1.05V      1.081V     1.282V
185ps     1.167V     1.08V      1.331V
210ps     1.285V     1.08V      1.377V
265ps     1.377V     1.278V     1.415V
305ps     1.395V     1.331V     1.422V
380ps     1.403V     1.347V     1.426V
1.575ns   1.404V     1.347V     1.427V
[Falling Waveform]
R_fixture = 50
V_fixture = 1.209
V_fixture_min = 1.214
V_fixture_max = 1.203
0s        1.405V     1.348V     1.428V
135ps     1.405V     1.348V     1.44V
170ps     1.412V     1.348V     1.157V
195ps     1.232V     1.348V     1.069V
215ps     1.145V     1.355V     1.033V
225ps     1.117V     1.352V     1.021V
275ps     1.047V     1.175V     991.2mV
345ps     1.022V     1.105V     981.3mV
450ps     1.014V     1.086V     978.6mV
1.575ns   1.013V     1.08V      977.9mV
